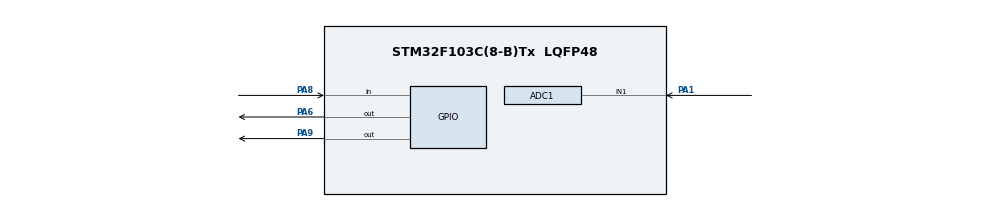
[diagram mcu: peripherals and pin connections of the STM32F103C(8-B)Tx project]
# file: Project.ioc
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ADC1.Channel-0\#ChannelRegularConversion=ADC_CHANNEL_1
ADC1.NbrOfConversionFlag=1
ADC1.Rank-0\#ChannelRegularConversion=1
ADC1.SamplingTime-0\#ChannelRegularConversion=ADC_SAMPLETIME_1CYCLE_5
ADC1.master=1
Mcu.Family=STM32F1
Mcu.Name=STM32F103C(8-B)Tx
Mcu.Package=LQFP48
NVIC.PriorityGroup=NVIC_PRIORITYGROUP_4
PA1.Signal=ADCx_IN1
PA13.Mode=Serial_Wire
PA13.Signal=SYS_JTMS-SWDIO
PA14.Mode=Serial_Wire
PA14.Signal=SYS_JTCK-SWCLK
PA6.Signal=GPIO_Output
PA8.Signal=GPIO_Input
PA9.Signal=GPIO_Output
PD0-OSC_IN.Mode=HSE-External-Oscillator
PD0-OSC_IN.Signal=RCC_OSC_IN
PD1-OSC_OUT.Mode=HSE-External-Oscillator
PD1-OSC_OUT.Signal=RCC_OSC_OUT
ProjectManager.HeapSize=0x200
ProjectManager.StackSize=0x400
ProjectManager.TargetToolchain=STM32CubeIDE
RCC.ADCPresc=RCC_ADCPCLK2_DIV6
RCC.AHBFreq_Value=64000000
RCC.APB1CLKDivider=RCC_HCLK_DIV2
RCC.APB1Freq_Value=32000000
RCC.APB1TimFreq_Value=64000000
RCC.APB2Freq_Value=64000000
RCC.APB2TimFreq_Value=64000000
RCC.HCLKFreq_Value=64000000
RCC.PLLMUL=RCC_PLL_MUL16
RCC.SYSCLKFreq_VALUE=64000000
RCC.SYSCLKSource=RCC_SYSCLKSOURCE_PLLCLK
RCC.USBFreq_Value=64000000
SH.ADCx_IN1.0=ADC1_IN1,IN1
TIM1.Prescaler=63
VP_TIM1_VS_ClockSourceINT.Mode=Internal
board=custom

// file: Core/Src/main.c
/* USER CODE BEGIN Header */
/**
  ******************************************************************************
  * @file           : main.c
  * @brief          : Smart Street Light - LDR + Sonar (No OLED)
  ******************************************************************************
  */
/* USER CODE END Header */

#include "main.h"

ADC_HandleTypeDef hadc1;
TIM_HandleTypeDef htim1;

/* USER CODE BEGIN PV */
#define TRIG_PIN GPIO_PIN_9
#define TRIG_PORT GPIOA
#define ECHO_PIN GPIO_PIN_8
#define ECHO_PORT GPIOA

uint32_t ldr_val = 0;
uint32_t pMillis;
uint32_t Value1 = 0;
uint32_t Value2 = 0;
uint16_t Distance  = 0;
/* USER CODE END PV */

/* Function Prototypes */
void SystemClock_Config(void);
static void MX_GPIO_Init(void);
static void MX_TIM1_Init(void);
static void MX_ADC1_Init(void);

int main(void)
{
  HAL_Init();
  SystemClock_Config();

  /* Initialize peripherals */
  MX_GPIO_Init();
  MX_TIM1_Init();
  MX_ADC1_Init();

  /* USER CODE BEGIN 2 */
  HAL_TIM_Base_Start(&htim1);
  HAL_GPIO_WritePin(TRIG_PORT, TRIG_PIN, GPIO_PIN_RESET);

  // Ensure Street Light starts OFF (PC13 SET = OFF)
  HAL_GPIO_WritePin(GPIOC, GPIO_PIN_13, GPIO_PIN_SET);
  /* USER CODE END 2 */

  while (1)
  {
    // --- STEP 1: CHECK LIGHT LEVEL ---
    HAL_ADC_Start(&hadc1);
    if (HAL_ADC_PollForConversion(&hadc1, 10) == HAL_OK)
    {
      ldr_val = HAL_ADC_GetValue(&hadc1);
    }
    HAL_ADC_Stop(&hadc1);

    // --- STEP 2: LOGIC BRANCHING ---
    if (ldr_val > 3000) // NIGHTTIME detected
    {
      // TRIGGER SONAR SENSOR
      HAL_GPIO_WritePin(TRIG_PORT, TRIG_PIN, GPIO_PIN_SET);
      __HAL_TIM_SET_COUNTER(&htim1, 0);
      while (__HAL_TIM_GET_COUNTER (&htim1) < 10);
      HAL_GPIO_WritePin(TRIG_PORT, TRIG_PIN, GPIO_PIN_RESET);

      pMillis = HAL_GetTick();
      // Wait for echo to go HIGH
      while (!(HAL_GPIO_ReadPin (ECHO_PORT, ECHO_PIN)) && pMillis + 10 > HAL_GetTick());
      Value1 = __HAL_TIM_GET_COUNTER (&htim1);

      pMillis = HAL_GetTick();
      // Wait for echo to go LOW
      while ((HAL_GPIO_ReadPin (ECHO_PORT, ECHO_PIN)) && pMillis + 50 > HAL_GetTick());
      Value2 = __HAL_TIM_GET_COUNTER (&htim1);

      Distance = (Value2 - Value1) * 0.034 / 2;

      // STREET LIGHT CONTROL (Presence Detection)
      // STREET LIGHT CONTROL
      if (Distance > 0 && Distance < 20)
      {
              HAL_GPIO_WritePin(GPIOC, GPIO_PIN_13, GPIO_PIN_RESET); // Internal LED ON
              HAL_GPIO_WritePin(GPIOA, GPIO_PIN_6, GPIO_PIN_SET);    // External LED ON (PA6)
              HAL_Delay(3000);
            }
            else
            {
              HAL_GPIO_WritePin(GPIOC, GPIO_PIN_13, GPIO_PIN_SET);   // Internal LED OFF
              HAL_GPIO_WritePin(GPIOA, GPIO_PIN_6, GPIO_PIN_RESET);  // External LED OFF (PA6)
      }
    }
    else // DAYTIME
    {
      // Force light OFF regardless of sonar
      HAL_GPIO_WritePin(GPIOC, GPIO_PIN_13, GPIO_PIN_SET);
    }

    HAL_Delay(100);
  }
}

/** * Peripherals configurations below
  **/

static void MX_ADC1_Init(void)
{
  ADC_ChannelConfTypeDef sConfig = {0};
  hadc1.Instance = ADC1;
  hadc1.Init.ScanConvMode = ADC_SCAN_DISABLE;
  hadc1.Init.ContinuousConvMode = DISABLE;
  hadc1.Init.DiscontinuousConvMode = DISABLE;
  hadc1.Init.ExternalTrigConv = ADC_SOFTWARE_START;
  hadc1.Init.DataAlign = ADC_DATAALIGN_RIGHT;
  hadc1.Init.NbrOfConversion = 1;
  HAL_ADC_Init(&hadc1);

  sConfig.Channel = ADC_CHANNEL_1;
  sConfig.Rank = ADC_REGULAR_RANK_1;
  sConfig.SamplingTime = ADC_SAMPLETIME_1CYCLE_5;
  HAL_ADC_ConfigChannel(&hadc1, &sConfig);
}

static void MX_TIM1_Init(void)
{
  htim1.Instance = TIM1;
  htim1.Init.Prescaler = 63; // 72MHz / 72 = 1MHz (1us per tick)
  htim1.Init.CounterMode = TIM_COUNTERMODE_UP;
  htim1.Init.Period = 65535;
  HAL_TIM_Base_Init(&htim1);
}

static void MX_GPIO_Init(void)
{
  GPIO_InitTypeDef GPIO_InitStruct = {0};

  /* GPIO Ports Clock Enable */
  __HAL_RCC_GPIOC_CLK_ENABLE();
  __HAL_RCC_GPIOA_CLK_ENABLE();

  /* Set initial states: Trig Low, Ext LED Low, Internal LED High (OFF) */
  HAL_GPIO_WritePin(GPIOA, GPIO_PIN_9 | GPIO_PIN_6, GPIO_PIN_RESET);
  HAL_GPIO_WritePin(GPIOC, GPIO_PIN_13, GPIO_PIN_SET);

  /* Configure PA8 as Echo (Input) */
  GPIO_InitStruct.Pin = GPIO_PIN_8;
  GPIO_InitStruct.Mode = GPIO_MODE_INPUT;
  GPIO_InitStruct.Pull = GPIO_NOPULL;
  HAL_GPIO_Init(GPIOA, &GPIO_InitStruct);

  /* Configure PA9 (Trig) AND PA6 (External LED) as Outputs */
  GPIO_InitStruct.Pin = GPIO_PIN_9 | GPIO_PIN_6;
  GPIO_InitStruct.Mode = GPIO_MODE_OUTPUT_PP;
  GPIO_InitStruct.Pull = GPIO_NOPULL;
  GPIO_InitStruct.Speed = GPIO_SPEED_FREQ_LOW;
  HAL_GPIO_Init(GPIOA, &GPIO_InitStruct);

  /* Configure PC13 as Internal LED (Output) */
  GPIO_InitStruct.Pin = GPIO_PIN_13;
  GPIO_InitStruct.Mode = GPIO_MODE_OUTPUT_PP;
  HAL_GPIO_Init(GPIOC, &GPIO_InitStruct);
}

void SystemClock_Config(void)
{
  RCC_OscInitTypeDef RCC_OscInitStruct = {0};
  RCC_ClkInitTypeDef RCC_ClkInitStruct = {0};

  RCC_OscInitStruct.OscillatorType = RCC_OSCILLATORTYPE_HSE;
  RCC_OscInitStruct.HSEState = RCC_HSE_ON;
  RCC_OscInitStruct.HSEPredivValue = RCC_HSE_PREDIV_DIV1;
  RCC_OscInitStruct.HSIState = RCC_HSI_ON;
  RCC_OscInitStruct.PLL.PLLState = RCC_PLL_ON;
  RCC_OscInitStruct.PLL.PLLSource = RCC_PLLSOURCE_HSE;
  RCC_OscInitStruct.PLL.PLLMUL = RCC_PLL_MUL9;
  HAL_RCC_OscConfig(&RCC_OscInitStruct);

  RCC_ClkInitStruct.ClockType = RCC_CLOCKTYPE_HCLK|RCC_CLOCKTYPE_SYSCLK
                              |RCC_CLOCKTYPE_PCLK1|RCC_CLOCKTYPE_PCLK2;
  RCC_ClkInitStruct.SYSCLKSource = RCC_SYSCLKSOURCE_PLLCLK;
  RCC_ClkInitStruct.AHBCLKDivider = RCC_SYSCLK_DIV1;
  RCC_ClkInitStruct.APB1CLKDivider = RCC_HCLK_DIV2;
  RCC_ClkInitStruct.APB2CLKDivider = RCC_HCLK_DIV1;
  HAL_RCC_ClockConfig(&RCC_ClkInitStruct, FLASH_LATENCY_2);
}

void Error_Handler(void)
{
  while (1) {}
}
